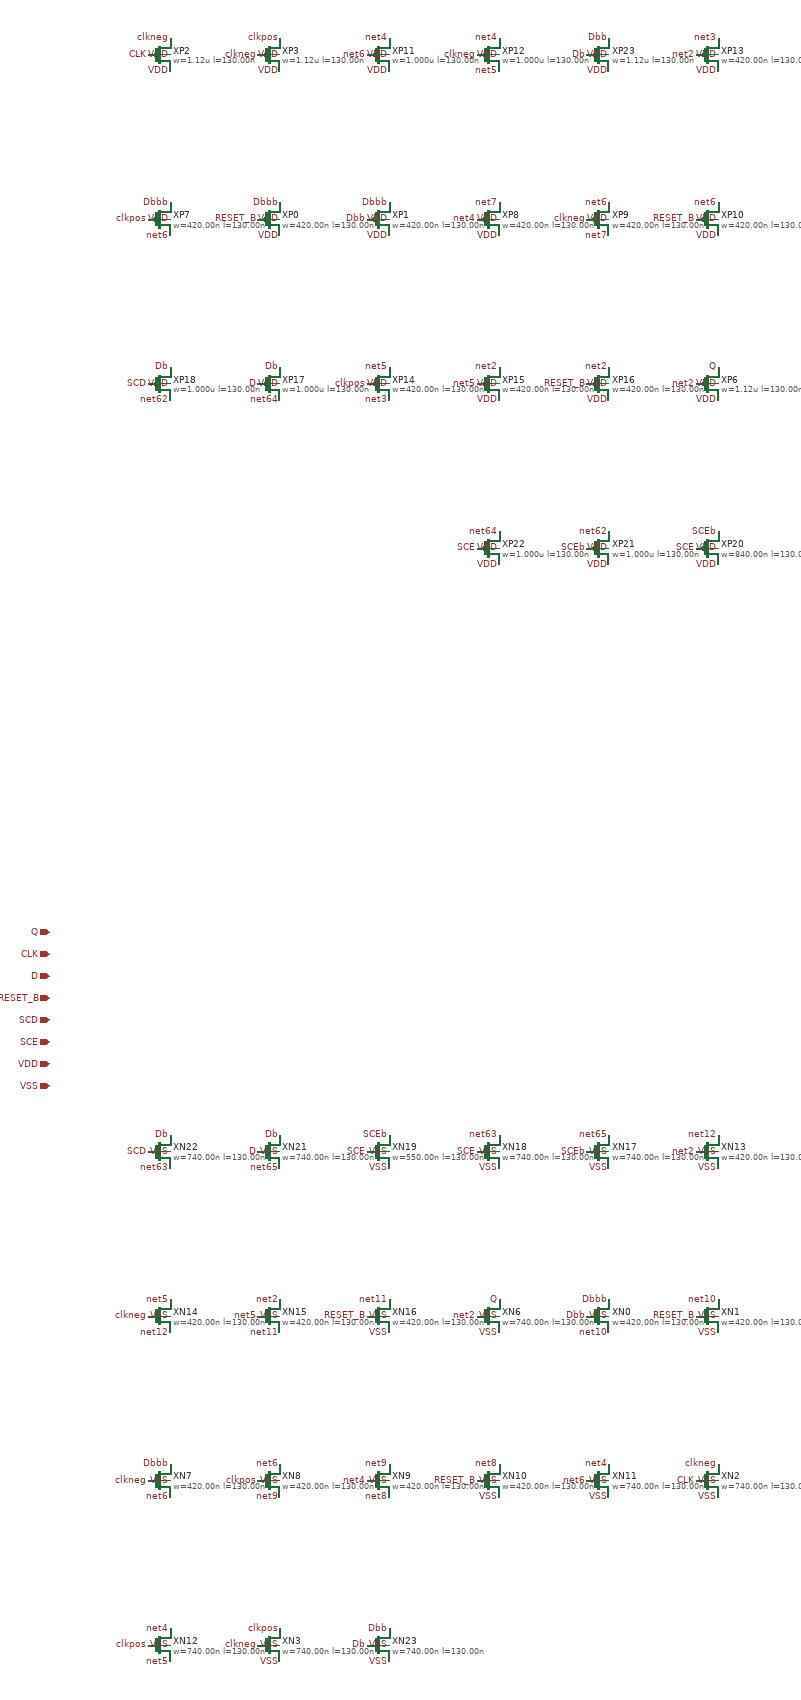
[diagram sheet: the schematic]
v {xschem version=3.4.5 file_version=1.2}
G {}
K {}
V {}
S {}
E {}
C {devices/ipin.sym} -200 -300 0 0 {name=pQ lab=Q}
C {devices/ipin.sym} -200 -260 0 0 {name=pCLK lab=CLK}
C {devices/ipin.sym} -200 -220 0 0 {name=pD lab=D}
C {devices/ipin.sym} -200 -180 0 0 {name=pRESET_B lab=RESET_B}
C {devices/ipin.sym} -200 -140 0 0 {name=pSCD lab=SCD}
C {devices/ipin.sym} -200 -100 0 0 {name=pSCE lab=SCE}
C {devices/ipin.sym} -200 -60 0 0 {name=pVDD lab=VDD}
C {devices/ipin.sym} -200 -20 0 0 {name=pVSS lab=VSS}
C {sg13g2_pr/sg13_lv_nmos.sym} 0 100 0 0 {name=XN22 model=sg13_lv_nmos spiceprefix=X w=740.00n l=130.00n ng=1 ad=2.516e-13 as=2.516e-13 pd=2.16e-06 ps=2.16e-06 m=1 }
C {devices/lab_pin.sym} 20 70 0 0 {lab=Db}
C {devices/lab_pin.sym} -20 100 0 0 {lab=SCD}
C {devices/lab_pin.sym} 20 130 0 0 {lab=net63}
C {devices/lab_pin.sym} 20 100 0 0 {lab=VSS}
C {sg13g2_pr/sg13_lv_nmos.sym} 200 100 0 0 {name=XN21 model=sg13_lv_nmos spiceprefix=X w=740.00n l=130.00n ng=1 ad=2.516e-13 as=2.516e-13 pd=2.16e-06 ps=2.16e-06 m=1 }
C {devices/lab_pin.sym} 220 70 0 0 {lab=Db}
C {devices/lab_pin.sym} 180 100 0 0 {lab=D}
C {devices/lab_pin.sym} 220 130 0 0 {lab=net65}
C {devices/lab_pin.sym} 220 100 0 0 {lab=VSS}
C {sg13g2_pr/sg13_lv_nmos.sym} 400 100 0 0 {name=XN19 model=sg13_lv_nmos spiceprefix=X w=550.00n l=130.00n ng=1 ad=1.87e-13 as=1.87e-13 pd=1.78e-06 ps=1.78e-06 m=1 }
C {devices/lab_pin.sym} 420 70 0 0 {lab=SCEb}
C {devices/lab_pin.sym} 380 100 0 0 {lab=SCE}
C {devices/lab_pin.sym} 420 130 0 0 {lab=VSS}
C {devices/lab_pin.sym} 420 100 0 0 {lab=VSS}
C {sg13g2_pr/sg13_lv_nmos.sym} 600 100 0 0 {name=XN18 model=sg13_lv_nmos spiceprefix=X w=740.00n l=130.00n ng=1 ad=2.516e-13 as=2.516e-13 pd=2.16e-06 ps=2.16e-06 m=1 }
C {devices/lab_pin.sym} 620 70 0 0 {lab=net63}
C {devices/lab_pin.sym} 580 100 0 0 {lab=SCE}
C {devices/lab_pin.sym} 620 130 0 0 {lab=VSS}
C {devices/lab_pin.sym} 620 100 0 0 {lab=VSS}
C {sg13g2_pr/sg13_lv_nmos.sym} 800 100 0 0 {name=XN17 model=sg13_lv_nmos spiceprefix=X w=740.00n l=130.00n ng=1 ad=2.516e-13 as=2.516e-13 pd=2.16e-06 ps=2.16e-06 m=1 }
C {devices/lab_pin.sym} 820 70 0 0 {lab=net65}
C {devices/lab_pin.sym} 780 100 0 0 {lab=SCEb}
C {devices/lab_pin.sym} 820 130 0 0 {lab=VSS}
C {devices/lab_pin.sym} 820 100 0 0 {lab=VSS}
C {sg13g2_pr/sg13_lv_nmos.sym} 1000 100 0 0 {name=XN13 model=sg13_lv_nmos spiceprefix=X w=420.00n l=130.00n ng=1 ad=1.428e-13 as=1.428e-13 pd=1.52e-06 ps=1.52e-06 m=1 }
C {devices/lab_pin.sym} 1020 70 0 0 {lab=net12}
C {devices/lab_pin.sym} 980 100 0 0 {lab=net2}
C {devices/lab_pin.sym} 1020 130 0 0 {lab=VSS}
C {devices/lab_pin.sym} 1020 100 0 0 {lab=VSS}
C {sg13g2_pr/sg13_lv_nmos.sym} 0 400 0 0 {name=XN14 model=sg13_lv_nmos spiceprefix=X w=420.00n l=130.00n ng=1 ad=1.428e-13 as=1.428e-13 pd=1.52e-06 ps=1.52e-06 m=1 }
C {devices/lab_pin.sym} 20 370 0 0 {lab=net5}
C {devices/lab_pin.sym} -20 400 0 0 {lab=clkneg}
C {devices/lab_pin.sym} 20 430 0 0 {lab=net12}
C {devices/lab_pin.sym} 20 400 0 0 {lab=VSS}
C {sg13g2_pr/sg13_lv_nmos.sym} 200 400 0 0 {name=XN15 model=sg13_lv_nmos spiceprefix=X w=420.00n l=130.00n ng=1 ad=1.428e-13 as=1.428e-13 pd=1.52e-06 ps=1.52e-06 m=1 }
C {devices/lab_pin.sym} 220 370 0 0 {lab=net2}
C {devices/lab_pin.sym} 180 400 0 0 {lab=net5}
C {devices/lab_pin.sym} 220 430 0 0 {lab=net11}
C {devices/lab_pin.sym} 220 400 0 0 {lab=VSS}
C {sg13g2_pr/sg13_lv_nmos.sym} 400 400 0 0 {name=XN16 model=sg13_lv_nmos spiceprefix=X w=420.00n l=130.00n ng=1 ad=1.428e-13 as=1.428e-13 pd=1.52e-06 ps=1.52e-06 m=1 }
C {devices/lab_pin.sym} 420 370 0 0 {lab=net11}
C {devices/lab_pin.sym} 380 400 0 0 {lab=RESET_B}
C {devices/lab_pin.sym} 420 430 0 0 {lab=VSS}
C {devices/lab_pin.sym} 420 400 0 0 {lab=VSS}
C {sg13g2_pr/sg13_lv_nmos.sym} 600 400 0 0 {name=XN6 model=sg13_lv_nmos spiceprefix=X w=740.00n l=130.00n ng=1 ad=2.516e-13 as=2.516e-13 pd=2.16e-06 ps=2.16e-06 m=1 }
C {devices/lab_pin.sym} 620 370 0 0 {lab=Q}
C {devices/lab_pin.sym} 580 400 0 0 {lab=net2}
C {devices/lab_pin.sym} 620 430 0 0 {lab=VSS}
C {devices/lab_pin.sym} 620 400 0 0 {lab=VSS}
C {sg13g2_pr/sg13_lv_nmos.sym} 800 400 0 0 {name=XN0 model=sg13_lv_nmos spiceprefix=X w=420.00n l=130.00n ng=1 ad=1.428e-13 as=1.428e-13 pd=1.52e-06 ps=1.52e-06 m=1 }
C {devices/lab_pin.sym} 820 370 0 0 {lab=Dbbb}
C {devices/lab_pin.sym} 780 400 0 0 {lab=Dbb}
C {devices/lab_pin.sym} 820 430 0 0 {lab=net10}
C {devices/lab_pin.sym} 820 400 0 0 {lab=VSS}
C {sg13g2_pr/sg13_lv_nmos.sym} 1000 400 0 0 {name=XN1 model=sg13_lv_nmos spiceprefix=X w=420.00n l=130.00n ng=1 ad=1.428e-13 as=1.428e-13 pd=1.52e-06 ps=1.52e-06 m=1 }
C {devices/lab_pin.sym} 1020 370 0 0 {lab=net10}
C {devices/lab_pin.sym} 980 400 0 0 {lab=RESET_B}
C {devices/lab_pin.sym} 1020 430 0 0 {lab=VSS}
C {devices/lab_pin.sym} 1020 400 0 0 {lab=VSS}
C {sg13g2_pr/sg13_lv_nmos.sym} 0 700 0 0 {name=XN7 model=sg13_lv_nmos spiceprefix=X w=420.00n l=130.00n ng=1 ad=1.428e-13 as=1.428e-13 pd=1.52e-06 ps=1.52e-06 m=1 }
C {devices/lab_pin.sym} 20 670 0 0 {lab=Dbbb}
C {devices/lab_pin.sym} -20 700 0 0 {lab=clkneg}
C {devices/lab_pin.sym} 20 730 0 0 {lab=net6}
C {devices/lab_pin.sym} 20 700 0 0 {lab=VSS}
C {sg13g2_pr/sg13_lv_nmos.sym} 200 700 0 0 {name=XN8 model=sg13_lv_nmos spiceprefix=X w=420.00n l=130.00n ng=1 ad=1.428e-13 as=1.428e-13 pd=1.52e-06 ps=1.52e-06 m=1 }
C {devices/lab_pin.sym} 220 670 0 0 {lab=net6}
C {devices/lab_pin.sym} 180 700 0 0 {lab=clkpos}
C {devices/lab_pin.sym} 220 730 0 0 {lab=net9}
C {devices/lab_pin.sym} 220 700 0 0 {lab=VSS}
C {sg13g2_pr/sg13_lv_nmos.sym} 400 700 0 0 {name=XN9 model=sg13_lv_nmos spiceprefix=X w=420.00n l=130.00n ng=1 ad=1.428e-13 as=1.428e-13 pd=1.52e-06 ps=1.52e-06 m=1 }
C {devices/lab_pin.sym} 420 670 0 0 {lab=net9}
C {devices/lab_pin.sym} 380 700 0 0 {lab=net4}
C {devices/lab_pin.sym} 420 730 0 0 {lab=net8}
C {devices/lab_pin.sym} 420 700 0 0 {lab=VSS}
C {sg13g2_pr/sg13_lv_nmos.sym} 600 700 0 0 {name=XN10 model=sg13_lv_nmos spiceprefix=X w=420.00n l=130.00n ng=1 ad=1.428e-13 as=1.428e-13 pd=1.52e-06 ps=1.52e-06 m=1 }
C {devices/lab_pin.sym} 620 670 0 0 {lab=net8}
C {devices/lab_pin.sym} 580 700 0 0 {lab=RESET_B}
C {devices/lab_pin.sym} 620 730 0 0 {lab=VSS}
C {devices/lab_pin.sym} 620 700 0 0 {lab=VSS}
C {sg13g2_pr/sg13_lv_nmos.sym} 800 700 0 0 {name=XN11 model=sg13_lv_nmos spiceprefix=X w=740.00n l=130.00n ng=1 ad=2.516e-13 as=2.516e-13 pd=2.16e-06 ps=2.16e-06 m=1 }
C {devices/lab_pin.sym} 820 670 0 0 {lab=net4}
C {devices/lab_pin.sym} 780 700 0 0 {lab=net6}
C {devices/lab_pin.sym} 820 730 0 0 {lab=VSS}
C {devices/lab_pin.sym} 820 700 0 0 {lab=VSS}
C {sg13g2_pr/sg13_lv_nmos.sym} 1000 700 0 0 {name=XN2 model=sg13_lv_nmos spiceprefix=X w=740.00n l=130.00n ng=1 ad=2.516e-13 as=2.516e-13 pd=2.16e-06 ps=2.16e-06 m=1 }
C {devices/lab_pin.sym} 1020 670 0 0 {lab=clkneg}
C {devices/lab_pin.sym} 980 700 0 0 {lab=CLK}
C {devices/lab_pin.sym} 1020 730 0 0 {lab=VSS}
C {devices/lab_pin.sym} 1020 700 0 0 {lab=VSS}
C {sg13g2_pr/sg13_lv_nmos.sym} 0 1000 0 0 {name=XN12 model=sg13_lv_nmos spiceprefix=X w=740.00n l=130.00n ng=1 ad=2.516e-13 as=2.516e-13 pd=2.16e-06 ps=2.16e-06 m=1 }
C {devices/lab_pin.sym} 20 970 0 0 {lab=net4}
C {devices/lab_pin.sym} -20 1000 0 0 {lab=clkpos}
C {devices/lab_pin.sym} 20 1030 0 0 {lab=net5}
C {devices/lab_pin.sym} 20 1000 0 0 {lab=VSS}
C {sg13g2_pr/sg13_lv_nmos.sym} 200 1000 0 0 {name=XN3 model=sg13_lv_nmos spiceprefix=X w=740.00n l=130.00n ng=1 ad=2.516e-13 as=2.516e-13 pd=2.16e-06 ps=2.16e-06 m=1 }
C {devices/lab_pin.sym} 220 970 0 0 {lab=clkpos}
C {devices/lab_pin.sym} 180 1000 0 0 {lab=clkneg}
C {devices/lab_pin.sym} 220 1030 0 0 {lab=VSS}
C {devices/lab_pin.sym} 220 1000 0 0 {lab=VSS}
C {sg13g2_pr/sg13_lv_nmos.sym} 400 1000 0 0 {name=XN23 model=sg13_lv_nmos spiceprefix=X w=740.00n l=130.00n ng=1 ad=2.516e-13 as=2.516e-13 pd=2.16e-06 ps=2.16e-06 m=1 }
C {devices/lab_pin.sym} 420 970 0 0 {lab=Dbb}
C {devices/lab_pin.sym} 380 1000 0 0 {lab=Db}
C {devices/lab_pin.sym} 420 1030 0 0 {lab=VSS}
C {devices/lab_pin.sym} 420 1000 0 0 {lab=VSS}
C {sg13g2_pr/sg13_lv_pmos.sym} 600 -1000 0 0 {name=XP22 model=sg13_lv_pmos spiceprefix=X w=1.000u l=130.00n ng=1 ad=3.4e-13 as=3.4e-13 pd=2.68e-06 ps=2.68e-06 m=1 }
C {devices/lab_pin.sym} 620 -1030 0 0 {lab=net64}
C {devices/lab_pin.sym} 580 -1000 0 0 {lab=SCE}
C {devices/lab_pin.sym} 620 -970 0 0 {lab=VDD}
C {devices/lab_pin.sym} 620 -1000 0 0 {lab=VDD}
C {sg13g2_pr/sg13_lv_pmos.sym} 800 -1000 0 0 {name=XP21 model=sg13_lv_pmos spiceprefix=X w=1.000u l=130.00n ng=1 ad=3.4e-13 as=3.4e-13 pd=2.68e-06 ps=2.68e-06 m=1 }
C {devices/lab_pin.sym} 820 -1030 0 0 {lab=net62}
C {devices/lab_pin.sym} 780 -1000 0 0 {lab=SCEb}
C {devices/lab_pin.sym} 820 -970 0 0 {lab=VDD}
C {devices/lab_pin.sym} 820 -1000 0 0 {lab=VDD}
C {sg13g2_pr/sg13_lv_pmos.sym} 1000 -1000 0 0 {name=XP20 model=sg13_lv_pmos spiceprefix=X w=840.00n l=130.00n ng=1 ad=2.856e-13 as=2.856e-13 pd=2.36e-06 ps=2.36e-06 m=1 }
C {devices/lab_pin.sym} 1020 -1030 0 0 {lab=SCEb}
C {devices/lab_pin.sym} 980 -1000 0 0 {lab=SCE}
C {devices/lab_pin.sym} 1020 -970 0 0 {lab=VDD}
C {devices/lab_pin.sym} 1020 -1000 0 0 {lab=VDD}
C {sg13g2_pr/sg13_lv_pmos.sym} 0 -1300 0 0 {name=XP18 model=sg13_lv_pmos spiceprefix=X w=1.000u l=130.00n ng=1 ad=3.4e-13 as=3.4e-13 pd=2.68e-06 ps=2.68e-06 m=1 }
C {devices/lab_pin.sym} 20 -1330 0 0 {lab=Db}
C {devices/lab_pin.sym} -20 -1300 0 0 {lab=SCD}
C {devices/lab_pin.sym} 20 -1270 0 0 {lab=net62}
C {devices/lab_pin.sym} 20 -1300 0 0 {lab=VDD}
C {sg13g2_pr/sg13_lv_pmos.sym} 200 -1300 0 0 {name=XP17 model=sg13_lv_pmos spiceprefix=X w=1.000u l=130.00n ng=1 ad=3.4e-13 as=3.4e-13 pd=2.68e-06 ps=2.68e-06 m=1 }
C {devices/lab_pin.sym} 220 -1330 0 0 {lab=Db}
C {devices/lab_pin.sym} 180 -1300 0 0 {lab=D}
C {devices/lab_pin.sym} 220 -1270 0 0 {lab=net64}
C {devices/lab_pin.sym} 220 -1300 0 0 {lab=VDD}
C {sg13g2_pr/sg13_lv_pmos.sym} 400 -1300 0 0 {name=XP14 model=sg13_lv_pmos spiceprefix=X w=420.00n l=130.00n ng=1 ad=1.428e-13 as=1.428e-13 pd=1.52e-06 ps=1.52e-06 m=1 }
C {devices/lab_pin.sym} 420 -1330 0 0 {lab=net5}
C {devices/lab_pin.sym} 380 -1300 0 0 {lab=clkpos}
C {devices/lab_pin.sym} 420 -1270 0 0 {lab=net3}
C {devices/lab_pin.sym} 420 -1300 0 0 {lab=VDD}
C {sg13g2_pr/sg13_lv_pmos.sym} 600 -1300 0 0 {name=XP15 model=sg13_lv_pmos spiceprefix=X w=420.00n l=130.00n ng=1 ad=1.428e-13 as=1.428e-13 pd=1.52e-06 ps=1.52e-06 m=1 }
C {devices/lab_pin.sym} 620 -1330 0 0 {lab=net2}
C {devices/lab_pin.sym} 580 -1300 0 0 {lab=net5}
C {devices/lab_pin.sym} 620 -1270 0 0 {lab=VDD}
C {devices/lab_pin.sym} 620 -1300 0 0 {lab=VDD}
C {sg13g2_pr/sg13_lv_pmos.sym} 800 -1300 0 0 {name=XP16 model=sg13_lv_pmos spiceprefix=X w=420.00n l=130.00n ng=1 ad=1.428e-13 as=1.428e-13 pd=1.52e-06 ps=1.52e-06 m=1 }
C {devices/lab_pin.sym} 820 -1330 0 0 {lab=net2}
C {devices/lab_pin.sym} 780 -1300 0 0 {lab=RESET_B}
C {devices/lab_pin.sym} 820 -1270 0 0 {lab=VDD}
C {devices/lab_pin.sym} 820 -1300 0 0 {lab=VDD}
C {sg13g2_pr/sg13_lv_pmos.sym} 1000 -1300 0 0 {name=XP6 model=sg13_lv_pmos spiceprefix=X w=1.12u l=130.00n ng=1 ad=3.808e-13 as=3.808e-13 pd=2.92e-06 ps=2.92e-06 m=1 }
C {devices/lab_pin.sym} 1020 -1330 0 0 {lab=Q}
C {devices/lab_pin.sym} 980 -1300 0 0 {lab=net2}
C {devices/lab_pin.sym} 1020 -1270 0 0 {lab=VDD}
C {devices/lab_pin.sym} 1020 -1300 0 0 {lab=VDD}
C {sg13g2_pr/sg13_lv_pmos.sym} 0 -1600 0 0 {name=XP7 model=sg13_lv_pmos spiceprefix=X w=420.00n l=130.00n ng=1 ad=1.428e-13 as=1.428e-13 pd=1.52e-06 ps=1.52e-06 m=1 }
C {devices/lab_pin.sym} 20 -1630 0 0 {lab=Dbbb}
C {devices/lab_pin.sym} -20 -1600 0 0 {lab=clkpos}
C {devices/lab_pin.sym} 20 -1570 0 0 {lab=net6}
C {devices/lab_pin.sym} 20 -1600 0 0 {lab=VDD}
C {sg13g2_pr/sg13_lv_pmos.sym} 200 -1600 0 0 {name=XP0 model=sg13_lv_pmos spiceprefix=X w=420.00n l=130.00n ng=1 ad=1.428e-13 as=1.428e-13 pd=1.52e-06 ps=1.52e-06 m=1 }
C {devices/lab_pin.sym} 220 -1630 0 0 {lab=Dbbb}
C {devices/lab_pin.sym} 180 -1600 0 0 {lab=RESET_B}
C {devices/lab_pin.sym} 220 -1570 0 0 {lab=VDD}
C {devices/lab_pin.sym} 220 -1600 0 0 {lab=VDD}
C {sg13g2_pr/sg13_lv_pmos.sym} 400 -1600 0 0 {name=XP1 model=sg13_lv_pmos spiceprefix=X w=420.00n l=130.00n ng=1 ad=1.428e-13 as=1.428e-13 pd=1.52e-06 ps=1.52e-06 m=1 }
C {devices/lab_pin.sym} 420 -1630 0 0 {lab=Dbbb}
C {devices/lab_pin.sym} 380 -1600 0 0 {lab=Dbb}
C {devices/lab_pin.sym} 420 -1570 0 0 {lab=VDD}
C {devices/lab_pin.sym} 420 -1600 0 0 {lab=VDD}
C {sg13g2_pr/sg13_lv_pmos.sym} 600 -1600 0 0 {name=XP8 model=sg13_lv_pmos spiceprefix=X w=420.00n l=130.00n ng=1 ad=1.428e-13 as=1.428e-13 pd=1.52e-06 ps=1.52e-06 m=1 }
C {devices/lab_pin.sym} 620 -1630 0 0 {lab=net7}
C {devices/lab_pin.sym} 580 -1600 0 0 {lab=net4}
C {devices/lab_pin.sym} 620 -1570 0 0 {lab=VDD}
C {devices/lab_pin.sym} 620 -1600 0 0 {lab=VDD}
C {sg13g2_pr/sg13_lv_pmos.sym} 800 -1600 0 0 {name=XP9 model=sg13_lv_pmos spiceprefix=X w=420.00n l=130.00n ng=1 ad=1.428e-13 as=1.428e-13 pd=1.52e-06 ps=1.52e-06 m=1 }
C {devices/lab_pin.sym} 820 -1630 0 0 {lab=net6}
C {devices/lab_pin.sym} 780 -1600 0 0 {lab=clkneg}
C {devices/lab_pin.sym} 820 -1570 0 0 {lab=net7}
C {devices/lab_pin.sym} 820 -1600 0 0 {lab=VDD}
C {sg13g2_pr/sg13_lv_pmos.sym} 1000 -1600 0 0 {name=XP10 model=sg13_lv_pmos spiceprefix=X w=420.00n l=130.00n ng=1 ad=1.428e-13 as=1.428e-13 pd=1.52e-06 ps=1.52e-06 m=1 }
C {devices/lab_pin.sym} 1020 -1630 0 0 {lab=net6}
C {devices/lab_pin.sym} 980 -1600 0 0 {lab=RESET_B}
C {devices/lab_pin.sym} 1020 -1570 0 0 {lab=VDD}
C {devices/lab_pin.sym} 1020 -1600 0 0 {lab=VDD}
C {sg13g2_pr/sg13_lv_pmos.sym} 0 -1900 0 0 {name=XP2 model=sg13_lv_pmos spiceprefix=X w=1.12u l=130.00n ng=1 ad=3.808e-13 as=3.808e-13 pd=2.92e-06 ps=2.92e-06 m=1 }
C {devices/lab_pin.sym} 20 -1930 0 0 {lab=clkneg}
C {devices/lab_pin.sym} -20 -1900 0 0 {lab=CLK}
C {devices/lab_pin.sym} 20 -1870 0 0 {lab=VDD}
C {devices/lab_pin.sym} 20 -1900 0 0 {lab=VDD}
C {sg13g2_pr/sg13_lv_pmos.sym} 200 -1900 0 0 {name=XP3 model=sg13_lv_pmos spiceprefix=X w=1.12u l=130.00n ng=1 ad=3.808e-13 as=3.808e-13 pd=2.92e-06 ps=2.92e-06 m=1 }
C {devices/lab_pin.sym} 220 -1930 0 0 {lab=clkpos}
C {devices/lab_pin.sym} 180 -1900 0 0 {lab=clkneg}
C {devices/lab_pin.sym} 220 -1870 0 0 {lab=VDD}
C {devices/lab_pin.sym} 220 -1900 0 0 {lab=VDD}
C {sg13g2_pr/sg13_lv_pmos.sym} 400 -1900 0 0 {name=XP11 model=sg13_lv_pmos spiceprefix=X w=1.000u l=130.00n ng=1 ad=3.4e-13 as=3.4e-13 pd=2.68e-06 ps=2.68e-06 m=1 }
C {devices/lab_pin.sym} 420 -1930 0 0 {lab=net4}
C {devices/lab_pin.sym} 380 -1900 0 0 {lab=net6}
C {devices/lab_pin.sym} 420 -1870 0 0 {lab=VDD}
C {devices/lab_pin.sym} 420 -1900 0 0 {lab=VDD}
C {sg13g2_pr/sg13_lv_pmos.sym} 600 -1900 0 0 {name=XP12 model=sg13_lv_pmos spiceprefix=X w=1.000u l=130.00n ng=1 ad=3.4e-13 as=3.4e-13 pd=2.68e-06 ps=2.68e-06 m=1 }
C {devices/lab_pin.sym} 620 -1930 0 0 {lab=net4}
C {devices/lab_pin.sym} 580 -1900 0 0 {lab=clkneg}
C {devices/lab_pin.sym} 620 -1870 0 0 {lab=net5}
C {devices/lab_pin.sym} 620 -1900 0 0 {lab=VDD}
C {sg13g2_pr/sg13_lv_pmos.sym} 800 -1900 0 0 {name=XP23 model=sg13_lv_pmos spiceprefix=X w=1.12u l=130.00n ng=1 ad=3.808e-13 as=3.808e-13 pd=2.92e-06 ps=2.92e-06 m=1 }
C {devices/lab_pin.sym} 820 -1930 0 0 {lab=Dbb}
C {devices/lab_pin.sym} 780 -1900 0 0 {lab=Db}
C {devices/lab_pin.sym} 820 -1870 0 0 {lab=VDD}
C {devices/lab_pin.sym} 820 -1900 0 0 {lab=VDD}
C {sg13g2_pr/sg13_lv_pmos.sym} 1000 -1900 0 0 {name=XP13 model=sg13_lv_pmos spiceprefix=X w=420.00n l=130.00n ng=1 ad=1.428e-13 as=1.428e-13 pd=1.52e-06 ps=1.52e-06 m=1 }
C {devices/lab_pin.sym} 1020 -1930 0 0 {lab=net3}
C {devices/lab_pin.sym} 980 -1900 0 0 {lab=net2}
C {devices/lab_pin.sym} 1020 -1870 0 0 {lab=VDD}
C {devices/lab_pin.sym} 1020 -1900 0 0 {lab=VDD}
